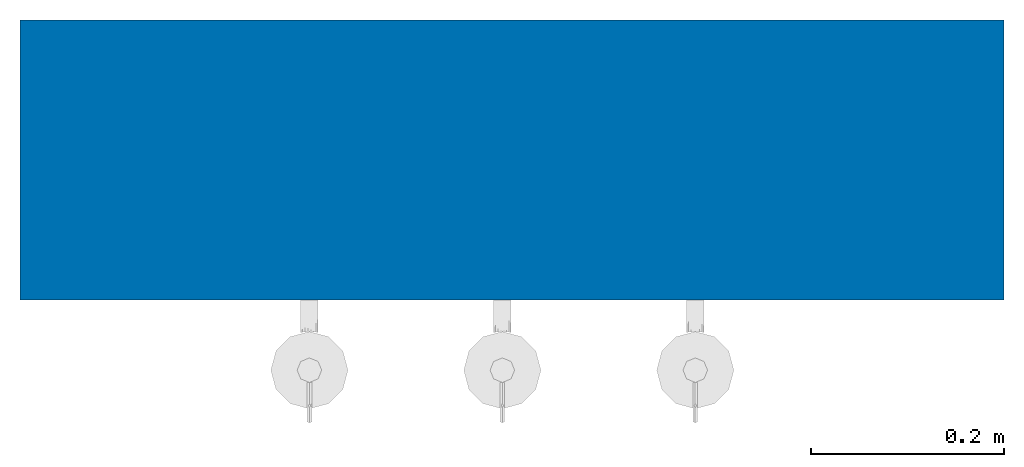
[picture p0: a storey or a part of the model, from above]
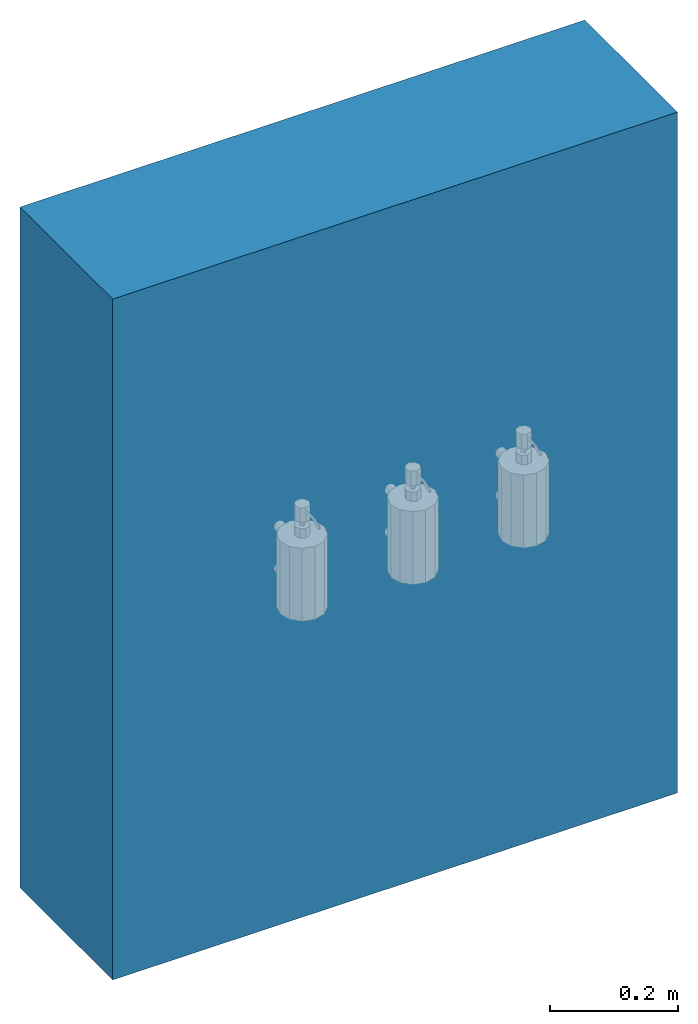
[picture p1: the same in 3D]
Properties of the parts of a building model (IFC2X3)

# File
Description: ViewDefinition [CoordinationView_V2.0]
File name: Project Number
Time: 2021-05-12T16:34:59
Written by: The EXPRESS Data Manager Version 5.02.0100.07 : 28 Aug 2013
Made in: 20170223_1515(x64) - Exporter 18.0.0.420 - Alternate UI 18.0.0.420
Comment: STEP Physical File produced by: The EXPRESS Data Manager Version 5.02.0100.07 : 28 Aug 2013 * Module: EDMstepFileFactory/EDMstandAlone * Creation date: Wed May 12 16:34:59 2021 * Host: DESKTOP-KN3O7NT * Database: C:\Users\SARAHS~1\AppData\Local\Temp\{CA250DD2-FD5E-488C-A683-04A9F46CAF6D}\ifc * Database version: 5507 * Database creation date: Wed May 12 16:34:56 2021 * Schema: IFC2X3 * Model: DataRepository.ifc * Model creation date: Wed May 12 16:34:57 2021 * Header model: DataRepository.ifc_HeaderModel * Header model creation date: Wed May 12 16:34:57 2021 * EDMuser: sdai-user * EDMgroup: sdai-group * License ID and type: 5605 : Permanent license. Expiry date: * EDMstepFileFactory options: 020000

# IfcProject, Project Number
LongName: Project Name; Phase: Project Status

# IfcSite, Default
RefLatitude: 51, 30, 23, 112487; RefLongitude: 0, -7, -37, -956022; RefElevation: 0 mm

# IfcBuilding
Pset_BuildingCommon - NumberOfStoreys: 1

# IfcBuildingStorey, Level 0
LongName: Level 0; Elevation: 0 mm

# IfcBuildingElementProxy: Brushed Stainless Steel, Duten_SoapDpnsrs_S210:Brushed Stainless Steel:315445
In: Level 0
Type - PredefinedType: USERDEFINED; Classification: E2020200 Furniture & Accessories (Uniformat); Material: Duten_Metal_BrushedStainlessSteel
Pset_BuildingElementProxyCommon - Reference: n/a
Pset_ManufacturerTypeInformation - ModelReference: Brushed Stainless Steel; Manufacturer: Duten

# IfcBuildingElementProxy: Matte Black Finish, Duten_SoapDpnsrs_S210:Matte Black Finish:315507
In: Level 0
Type - PredefinedType: USERDEFINED; Classification: E2020200 Furniture & Accessories (Uniformat); Material: Duten_Metal_MatteBlack
Pset_BuildingElementProxyCommon - Reference: n/a
Pset_ManufacturerTypeInformation - ModelReference: Matte Black Finish; Manufacturer: Duten

# IfcBuildingElementProxy: Polished Stainless Steel, Duten_SoapDpnsrs_S210:Polished Stainless Steel:315522
In: Level 0
Type - PredefinedType: USERDEFINED; Classification: E2020200 Furniture & Accessories (Uniformat); Material: Duten_Metal_Polished
Pset_BuildingElementProxyCommon - Reference: n/a
Pset_ManufacturerTypeInformation - ModelReference: Polished Stainless Steel; Manufacturer: Duten

# IfcWallStandardCase: Basic Wall:Wall-Ext_102Bwk-75Ins-100LBlk-12P, Basic Wall:Wall-Ext_102Bwk-75Ins-100LBlk-12P:310501
In: Level 0
Type - PredefinedType: STANDARD; Material: Brick, Common 102.5 mm, Fiberglass Batt 75 mm, Concrete Masonry Units _Low Density 100 mm, Plaster 12.5 mm
Pset_WallCommon - Reference: Wall-Ext_102Bwk-75Ins-100LBlk-12P; LoadBearing: no; ExtendToStructure: no; IsExternal: yes; ThermalTransmittance: 0.235926 kg/K/s3
